VERSION 5.7 ;
  NOWIREEXTENSIONATPIN ON ;
  DIVIDERCHAR "/" ;
  BUSBITCHARS "[]" ;
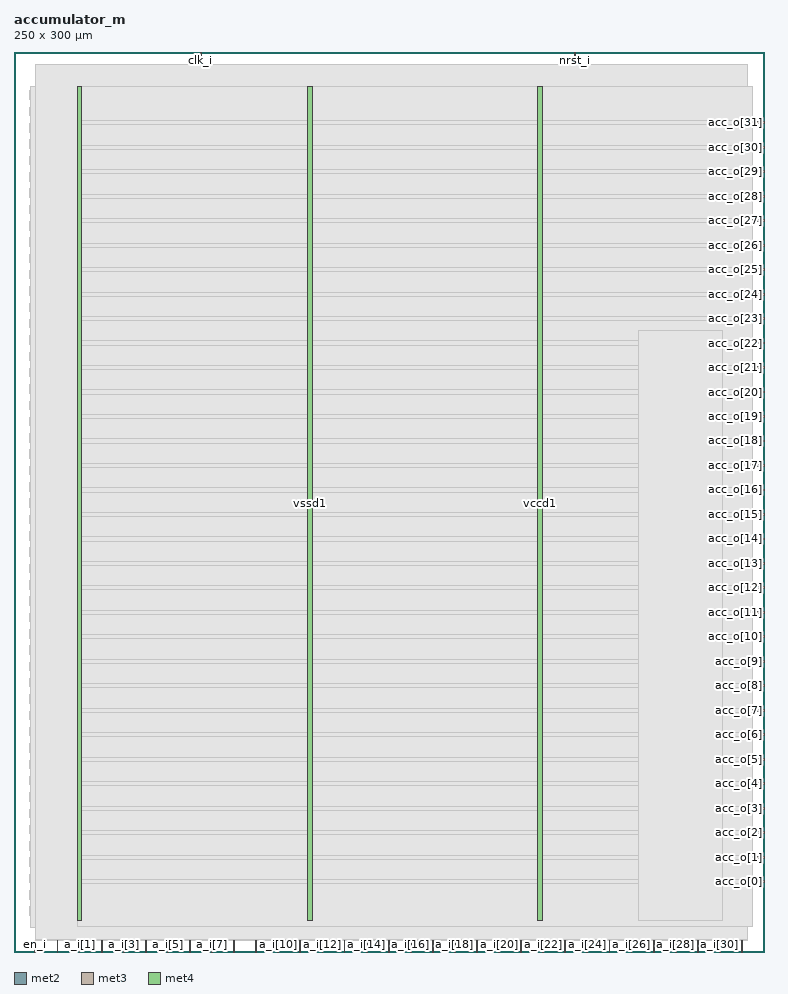
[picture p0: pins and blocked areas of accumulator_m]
MACRO accumulator_m
  CLASS BLOCK ;
  FOREIGN accumulator_m ;
  ORIGIN 0.000 0.000 ;
  SIZE 250.000 BY 300.000 ;
  PIN a_i[0]
    DIRECTION INPUT ;
    USE SIGNAL ;
    ANTENNAGATEAREA 0.213000 ;
    PORT
      LAYER met2 ;
        RECT 14.350 0.000 14.630 4.000 ;
    END
  END a_i[0]
  PIN a_i[10]
    DIRECTION INPUT ;
    USE SIGNAL ;
    ANTENNAGATEAREA 0.213000 ;
    PORT
      LAYER met2 ;
        RECT 87.950 0.000 88.230 4.000 ;
    END
  END a_i[10]
  PIN a_i[11]
    DIRECTION INPUT ;
    USE SIGNAL ;
    ANTENNAGATEAREA 0.126000 ;
    PORT
      LAYER met2 ;
        RECT 95.310 0.000 95.590 4.000 ;
    END
  END a_i[11]
  PIN a_i[12]
    DIRECTION INPUT ;
    USE SIGNAL ;
    ANTENNAGATEAREA 0.213000 ;
    PORT
      LAYER met2 ;
        RECT 102.670 0.000 102.950 4.000 ;
    END
  END a_i[12]
  PIN a_i[13]
    DIRECTION INPUT ;
    USE SIGNAL ;
    ANTENNAGATEAREA 0.213000 ;
    PORT
      LAYER met2 ;
        RECT 110.030 0.000 110.310 4.000 ;
    END
  END a_i[13]
  PIN a_i[14]
    DIRECTION INPUT ;
    USE SIGNAL ;
    ANTENNAGATEAREA 0.213000 ;
    PORT
      LAYER met2 ;
        RECT 117.390 0.000 117.670 4.000 ;
    END
  END a_i[14]
  PIN a_i[15]
    DIRECTION INPUT ;
    USE SIGNAL ;
    ANTENNAGATEAREA 0.213000 ;
    PORT
      LAYER met2 ;
        RECT 124.750 0.000 125.030 4.000 ;
    END
  END a_i[15]
  PIN a_i[16]
    DIRECTION INPUT ;
    USE SIGNAL ;
    ANTENNAGATEAREA 0.213000 ;
    PORT
      LAYER met2 ;
        RECT 132.110 0.000 132.390 4.000 ;
    END
  END a_i[16]
  PIN a_i[17]
    DIRECTION INPUT ;
    USE SIGNAL ;
    ANTENNAGATEAREA 0.213000 ;
    PORT
      LAYER met2 ;
        RECT 139.470 0.000 139.750 4.000 ;
    END
  END a_i[17]
  PIN a_i[18]
    DIRECTION INPUT ;
    USE SIGNAL ;
    ANTENNAGATEAREA 0.213000 ;
    PORT
      LAYER met2 ;
        RECT 146.830 0.000 147.110 4.000 ;
    END
  END a_i[18]
  PIN a_i[19]
    DIRECTION INPUT ;
    USE SIGNAL ;
    ANTENNAGATEAREA 0.126000 ;
    PORT
      LAYER met2 ;
        RECT 154.190 0.000 154.470 4.000 ;
    END
  END a_i[19]
  PIN a_i[1]
    DIRECTION INPUT ;
    USE SIGNAL ;
    ANTENNAGATEAREA 0.213000 ;
    PORT
      LAYER met2 ;
        RECT 21.710 0.000 21.990 4.000 ;
    END
  END a_i[1]
  PIN a_i[20]
    DIRECTION INPUT ;
    USE SIGNAL ;
    ANTENNAGATEAREA 0.196500 ;
    PORT
      LAYER met2 ;
        RECT 161.550 0.000 161.830 4.000 ;
    END
  END a_i[20]
  PIN a_i[21]
    DIRECTION INPUT ;
    USE SIGNAL ;
    ANTENNAGATEAREA 0.196500 ;
    PORT
      LAYER met2 ;
        RECT 168.910 0.000 169.190 4.000 ;
    END
  END a_i[21]
  PIN a_i[22]
    DIRECTION INPUT ;
    USE SIGNAL ;
    ANTENNAGATEAREA 0.196500 ;
    PORT
      LAYER met2 ;
        RECT 176.270 0.000 176.550 4.000 ;
    END
  END a_i[22]
  PIN a_i[23]
    DIRECTION INPUT ;
    USE SIGNAL ;
    ANTENNAGATEAREA 0.196500 ;
    PORT
      LAYER met2 ;
        RECT 183.630 0.000 183.910 4.000 ;
    END
  END a_i[23]
  PIN a_i[24]
    DIRECTION INPUT ;
    USE SIGNAL ;
    ANTENNAGATEAREA 0.196500 ;
    PORT
      LAYER met2 ;
        RECT 190.990 0.000 191.270 4.000 ;
    END
  END a_i[24]
  PIN a_i[25]
    DIRECTION INPUT ;
    USE SIGNAL ;
    ANTENNAGATEAREA 0.126000 ;
    PORT
      LAYER met2 ;
        RECT 198.350 0.000 198.630 4.000 ;
    END
  END a_i[25]
  PIN a_i[26]
    DIRECTION INPUT ;
    USE SIGNAL ;
    ANTENNAGATEAREA 0.196500 ;
    PORT
      LAYER met2 ;
        RECT 205.710 0.000 205.990 4.000 ;
    END
  END a_i[26]
  PIN a_i[27]
    DIRECTION INPUT ;
    USE SIGNAL ;
    ANTENNAGATEAREA 0.126000 ;
    PORT
      LAYER met2 ;
        RECT 213.070 0.000 213.350 4.000 ;
    END
  END a_i[27]
  PIN a_i[28]
    DIRECTION INPUT ;
    USE SIGNAL ;
    ANTENNAGATEAREA 0.196500 ;
    PORT
      LAYER met2 ;
        RECT 220.430 0.000 220.710 4.000 ;
    END
  END a_i[28]
  PIN a_i[29]
    DIRECTION INPUT ;
    USE SIGNAL ;
    ANTENNAGATEAREA 0.126000 ;
    PORT
      LAYER met2 ;
        RECT 227.790 0.000 228.070 4.000 ;
    END
  END a_i[29]
  PIN a_i[2]
    DIRECTION INPUT ;
    USE SIGNAL ;
    ANTENNAGATEAREA 0.213000 ;
    PORT
      LAYER met2 ;
        RECT 29.070 0.000 29.350 4.000 ;
    END
  END a_i[2]
  PIN a_i[30]
    DIRECTION INPUT ;
    USE SIGNAL ;
    ANTENNAGATEAREA 0.196500 ;
    PORT
      LAYER met2 ;
        RECT 235.150 0.000 235.430 4.000 ;
    END
  END a_i[30]
  PIN a_i[31]
    DIRECTION INPUT ;
    USE SIGNAL ;
    ANTENNAGATEAREA 0.196500 ;
    PORT
      LAYER met2 ;
        RECT 242.510 0.000 242.790 4.000 ;
    END
  END a_i[31]
  PIN a_i[3]
    DIRECTION INPUT ;
    USE SIGNAL ;
    ANTENNAGATEAREA 0.213000 ;
    PORT
      LAYER met2 ;
        RECT 36.430 0.000 36.710 4.000 ;
    END
  END a_i[3]
  PIN a_i[4]
    DIRECTION INPUT ;
    USE SIGNAL ;
    ANTENNAGATEAREA 0.213000 ;
    PORT
      LAYER met2 ;
        RECT 43.790 0.000 44.070 4.000 ;
    END
  END a_i[4]
  PIN a_i[5]
    DIRECTION INPUT ;
    USE SIGNAL ;
    ANTENNAGATEAREA 0.213000 ;
    PORT
      LAYER met2 ;
        RECT 51.150 0.000 51.430 4.000 ;
    END
  END a_i[5]
  PIN a_i[6]
    DIRECTION INPUT ;
    USE SIGNAL ;
    ANTENNAGATEAREA 0.213000 ;
    PORT
      LAYER met2 ;
        RECT 58.510 0.000 58.790 4.000 ;
    END
  END a_i[6]
  PIN a_i[7]
    DIRECTION INPUT ;
    USE SIGNAL ;
    ANTENNAGATEAREA 0.159000 ;
    PORT
      LAYER met2 ;
        RECT 65.870 0.000 66.150 4.000 ;
    END
  END a_i[7]
  PIN a_i[8]
    DIRECTION INPUT ;
    USE SIGNAL ;
    ANTENNAGATEAREA 0.213000 ;
    PORT
      LAYER met2 ;
        RECT 73.230 0.000 73.510 4.000 ;
    END
  END a_i[8]
  PIN a_i[9]
    DIRECTION INPUT ;
    USE SIGNAL ;
    ANTENNAGATEAREA 0.213000 ;
    PORT
      LAYER met2 ;
        RECT 80.590 0.000 80.870 4.000 ;
    END
  END a_i[9]
  PIN acc_o[0]
    DIRECTION OUTPUT TRISTATE ;
    USE SIGNAL ;
    ANTENNADIFFAREA 2.673000 ;
    PORT
      LAYER met3 ;
        RECT 246.000 23.160 250.000 23.760 ;
    END
  END acc_o[0]
  PIN acc_o[10]
    DIRECTION OUTPUT TRISTATE ;
    USE SIGNAL ;
    ANTENNADIFFAREA 2.673000 ;
    PORT
      LAYER met3 ;
        RECT 246.000 104.760 250.000 105.360 ;
    END
  END acc_o[10]
  PIN acc_o[11]
    DIRECTION OUTPUT TRISTATE ;
    USE SIGNAL ;
    ANTENNADIFFAREA 2.673000 ;
    PORT
      LAYER met3 ;
        RECT 246.000 112.920 250.000 113.520 ;
    END
  END acc_o[11]
  PIN acc_o[12]
    DIRECTION OUTPUT TRISTATE ;
    USE SIGNAL ;
    ANTENNADIFFAREA 2.673000 ;
    PORT
      LAYER met3 ;
        RECT 246.000 121.080 250.000 121.680 ;
    END
  END acc_o[12]
  PIN acc_o[13]
    DIRECTION OUTPUT TRISTATE ;
    USE SIGNAL ;
    ANTENNADIFFAREA 2.673000 ;
    PORT
      LAYER met3 ;
        RECT 246.000 129.240 250.000 129.840 ;
    END
  END acc_o[13]
  PIN acc_o[14]
    DIRECTION OUTPUT TRISTATE ;
    USE SIGNAL ;
    ANTENNADIFFAREA 2.673000 ;
    PORT
      LAYER met3 ;
        RECT 246.000 137.400 250.000 138.000 ;
    END
  END acc_o[14]
  PIN acc_o[15]
    DIRECTION OUTPUT TRISTATE ;
    USE SIGNAL ;
    ANTENNADIFFAREA 2.673000 ;
    PORT
      LAYER met3 ;
        RECT 246.000 145.560 250.000 146.160 ;
    END
  END acc_o[15]
  PIN acc_o[16]
    DIRECTION OUTPUT TRISTATE ;
    USE SIGNAL ;
    ANTENNADIFFAREA 2.673000 ;
    PORT
      LAYER met3 ;
        RECT 246.000 153.720 250.000 154.320 ;
    END
  END acc_o[16]
  PIN acc_o[17]
    DIRECTION OUTPUT TRISTATE ;
    USE SIGNAL ;
    ANTENNADIFFAREA 2.673000 ;
    PORT
      LAYER met3 ;
        RECT 246.000 161.880 250.000 162.480 ;
    END
  END acc_o[17]
  PIN acc_o[18]
    DIRECTION OUTPUT TRISTATE ;
    USE SIGNAL ;
    ANTENNADIFFAREA 2.673000 ;
    PORT
      LAYER met3 ;
        RECT 246.000 170.040 250.000 170.640 ;
    END
  END acc_o[18]
  PIN acc_o[19]
    DIRECTION OUTPUT TRISTATE ;
    USE SIGNAL ;
    ANTENNADIFFAREA 2.673000 ;
    PORT
      LAYER met3 ;
        RECT 246.000 178.200 250.000 178.800 ;
    END
  END acc_o[19]
  PIN acc_o[1]
    DIRECTION OUTPUT TRISTATE ;
    USE SIGNAL ;
    ANTENNADIFFAREA 2.673000 ;
    PORT
      LAYER met3 ;
        RECT 246.000 31.320 250.000 31.920 ;
    END
  END acc_o[1]
  PIN acc_o[20]
    DIRECTION OUTPUT TRISTATE ;
    USE SIGNAL ;
    ANTENNADIFFAREA 2.673000 ;
    PORT
      LAYER met3 ;
        RECT 246.000 186.360 250.000 186.960 ;
    END
  END acc_o[20]
  PIN acc_o[21]
    DIRECTION OUTPUT TRISTATE ;
    USE SIGNAL ;
    ANTENNADIFFAREA 2.673000 ;
    PORT
      LAYER met3 ;
        RECT 246.000 194.520 250.000 195.120 ;
    END
  END acc_o[21]
  PIN acc_o[22]
    DIRECTION OUTPUT TRISTATE ;
    USE SIGNAL ;
    ANTENNADIFFAREA 2.673000 ;
    PORT
      LAYER met3 ;
        RECT 246.000 202.680 250.000 203.280 ;
    END
  END acc_o[22]
  PIN acc_o[23]
    DIRECTION OUTPUT TRISTATE ;
    USE SIGNAL ;
    ANTENNADIFFAREA 2.673000 ;
    PORT
      LAYER met3 ;
        RECT 246.000 210.840 250.000 211.440 ;
    END
  END acc_o[23]
  PIN acc_o[24]
    DIRECTION OUTPUT TRISTATE ;
    USE SIGNAL ;
    ANTENNADIFFAREA 2.673000 ;
    PORT
      LAYER met3 ;
        RECT 246.000 219.000 250.000 219.600 ;
    END
  END acc_o[24]
  PIN acc_o[25]
    DIRECTION OUTPUT TRISTATE ;
    USE SIGNAL ;
    ANTENNADIFFAREA 2.673000 ;
    PORT
      LAYER met3 ;
        RECT 246.000 227.160 250.000 227.760 ;
    END
  END acc_o[25]
  PIN acc_o[26]
    DIRECTION OUTPUT TRISTATE ;
    USE SIGNAL ;
    ANTENNADIFFAREA 2.673000 ;
    PORT
      LAYER met3 ;
        RECT 246.000 235.320 250.000 235.920 ;
    END
  END acc_o[26]
  PIN acc_o[27]
    DIRECTION OUTPUT TRISTATE ;
    USE SIGNAL ;
    ANTENNADIFFAREA 2.673000 ;
    PORT
      LAYER met3 ;
        RECT 246.000 243.480 250.000 244.080 ;
    END
  END acc_o[27]
  PIN acc_o[28]
    DIRECTION OUTPUT TRISTATE ;
    USE SIGNAL ;
    ANTENNADIFFAREA 2.673000 ;
    PORT
      LAYER met3 ;
        RECT 246.000 251.640 250.000 252.240 ;
    END
  END acc_o[28]
  PIN acc_o[29]
    DIRECTION OUTPUT TRISTATE ;
    USE SIGNAL ;
    ANTENNADIFFAREA 2.673000 ;
    PORT
      LAYER met3 ;
        RECT 246.000 259.800 250.000 260.400 ;
    END
  END acc_o[29]
  PIN acc_o[2]
    DIRECTION OUTPUT TRISTATE ;
    USE SIGNAL ;
    ANTENNADIFFAREA 2.673000 ;
    PORT
      LAYER met3 ;
        RECT 246.000 39.480 250.000 40.080 ;
    END
  END acc_o[2]
  PIN acc_o[30]
    DIRECTION OUTPUT TRISTATE ;
    USE SIGNAL ;
    ANTENNADIFFAREA 2.673000 ;
    PORT
      LAYER met3 ;
        RECT 246.000 267.960 250.000 268.560 ;
    END
  END acc_o[30]
  PIN acc_o[31]
    DIRECTION OUTPUT TRISTATE ;
    USE SIGNAL ;
    ANTENNADIFFAREA 2.673000 ;
    PORT
      LAYER met3 ;
        RECT 246.000 276.120 250.000 276.720 ;
    END
  END acc_o[31]
  PIN acc_o[3]
    DIRECTION OUTPUT TRISTATE ;
    USE SIGNAL ;
    ANTENNADIFFAREA 2.673000 ;
    PORT
      LAYER met3 ;
        RECT 246.000 47.640 250.000 48.240 ;
    END
  END acc_o[3]
  PIN acc_o[4]
    DIRECTION OUTPUT TRISTATE ;
    USE SIGNAL ;
    ANTENNADIFFAREA 2.673000 ;
    PORT
      LAYER met3 ;
        RECT 246.000 55.800 250.000 56.400 ;
    END
  END acc_o[4]
  PIN acc_o[5]
    DIRECTION OUTPUT TRISTATE ;
    USE SIGNAL ;
    ANTENNADIFFAREA 2.673000 ;
    PORT
      LAYER met3 ;
        RECT 246.000 63.960 250.000 64.560 ;
    END
  END acc_o[5]
  PIN acc_o[6]
    DIRECTION OUTPUT TRISTATE ;
    USE SIGNAL ;
    ANTENNADIFFAREA 2.673000 ;
    PORT
      LAYER met3 ;
        RECT 246.000 72.120 250.000 72.720 ;
    END
  END acc_o[6]
  PIN acc_o[7]
    DIRECTION OUTPUT TRISTATE ;
    USE SIGNAL ;
    ANTENNADIFFAREA 2.673000 ;
    PORT
      LAYER met3 ;
        RECT 246.000 80.280 250.000 80.880 ;
    END
  END acc_o[7]
  PIN acc_o[8]
    DIRECTION OUTPUT TRISTATE ;
    USE SIGNAL ;
    ANTENNADIFFAREA 2.673000 ;
    PORT
      LAYER met3 ;
        RECT 246.000 88.440 250.000 89.040 ;
    END
  END acc_o[8]
  PIN acc_o[9]
    DIRECTION OUTPUT TRISTATE ;
    USE SIGNAL ;
    ANTENNADIFFAREA 2.673000 ;
    PORT
      LAYER met3 ;
        RECT 246.000 96.600 250.000 97.200 ;
    END
  END acc_o[9]
  PIN clk_i
    DIRECTION INPUT ;
    USE SIGNAL ;
    ANTENNAGATEAREA 0.852000 ;
    PORT
      LAYER met2 ;
        RECT 62.190 296.000 62.470 300.000 ;
    END
  END clk_i
  PIN en_i
    DIRECTION INPUT ;
    USE SIGNAL ;
    ANTENNAGATEAREA 0.213000 ;
    PORT
      LAYER met2 ;
        RECT 6.990 0.000 7.270 4.000 ;
    END
  END en_i
  PIN nrst_i
    DIRECTION INPUT ;
    USE SIGNAL ;
    ANTENNAGATEAREA 0.213000 ;
    PORT
      LAYER met2 ;
        RECT 186.850 296.000 187.130 300.000 ;
    END
  END nrst_i
  PIN vccd1
    DIRECTION INOUT ;
    USE POWER ;
    PORT
      LAYER met4 ;
        RECT 21.040 10.640 22.640 288.560 ;
    END
    PORT
      LAYER met4 ;
        RECT 174.640 10.640 176.240 288.560 ;
    END
  END vccd1
  PIN vssd1
    DIRECTION INOUT ;
    USE GROUND ;
    PORT
      LAYER met4 ;
        RECT 97.840 10.640 99.440 288.560 ;
    END
  END vssd1
  OBS
      LAYER nwell ;
        RECT 5.330 284.185 244.450 287.015 ;
        RECT 5.330 278.745 244.450 281.575 ;
        RECT 5.330 273.305 244.450 276.135 ;
        RECT 5.330 267.865 244.450 270.695 ;
        RECT 5.330 262.425 244.450 265.255 ;
        RECT 5.330 256.985 244.450 259.815 ;
        RECT 5.330 251.545 244.450 254.375 ;
        RECT 5.330 246.105 244.450 248.935 ;
        RECT 5.330 240.665 244.450 243.495 ;
        RECT 5.330 235.225 244.450 238.055 ;
        RECT 5.330 229.785 244.450 232.615 ;
        RECT 5.330 224.345 244.450 227.175 ;
        RECT 5.330 218.905 244.450 221.735 ;
        RECT 5.330 213.465 244.450 216.295 ;
        RECT 5.330 208.025 244.450 210.855 ;
        RECT 5.330 202.585 244.450 205.415 ;
        RECT 5.330 197.145 244.450 199.975 ;
        RECT 5.330 191.705 244.450 194.535 ;
        RECT 5.330 186.265 244.450 189.095 ;
        RECT 5.330 180.825 244.450 183.655 ;
        RECT 5.330 175.385 244.450 178.215 ;
        RECT 5.330 169.945 244.450 172.775 ;
        RECT 5.330 164.505 244.450 167.335 ;
        RECT 5.330 159.065 244.450 161.895 ;
        RECT 5.330 153.625 244.450 156.455 ;
        RECT 5.330 148.185 244.450 151.015 ;
        RECT 5.330 142.745 244.450 145.575 ;
        RECT 5.330 137.305 244.450 140.135 ;
        RECT 5.330 131.865 244.450 134.695 ;
        RECT 5.330 126.425 244.450 129.255 ;
        RECT 5.330 120.985 244.450 123.815 ;
        RECT 5.330 115.545 244.450 118.375 ;
        RECT 5.330 110.105 244.450 112.935 ;
        RECT 5.330 104.665 244.450 107.495 ;
        RECT 5.330 99.225 244.450 102.055 ;
        RECT 5.330 93.785 244.450 96.615 ;
        RECT 5.330 88.345 244.450 91.175 ;
        RECT 5.330 82.905 244.450 85.735 ;
        RECT 5.330 77.465 244.450 80.295 ;
        RECT 5.330 72.025 244.450 74.855 ;
        RECT 5.330 66.585 244.450 69.415 ;
        RECT 5.330 61.145 244.450 63.975 ;
        RECT 5.330 55.705 244.450 58.535 ;
        RECT 5.330 50.265 244.450 53.095 ;
        RECT 5.330 44.825 244.450 47.655 ;
        RECT 5.330 39.385 244.450 42.215 ;
        RECT 5.330 33.945 244.450 36.775 ;
        RECT 5.330 28.505 244.450 31.335 ;
        RECT 5.330 23.065 244.450 25.895 ;
        RECT 5.330 17.625 244.450 20.455 ;
        RECT 5.330 12.185 244.450 15.015 ;
      LAYER li1 ;
        RECT 5.520 10.795 244.260 288.405 ;
      LAYER met1 ;
        RECT 5.520 8.200 244.560 288.560 ;
      LAYER met2 ;
        RECT 7.060 295.720 61.910 296.000 ;
        RECT 62.750 295.720 186.570 296.000 ;
        RECT 187.410 295.720 244.560 296.000 ;
        RECT 7.060 4.280 244.560 295.720 ;
        RECT 7.550 4.000 14.070 4.280 ;
        RECT 14.910 4.000 21.430 4.280 ;
        RECT 22.270 4.000 28.790 4.280 ;
        RECT 29.630 4.000 36.150 4.280 ;
        RECT 36.990 4.000 43.510 4.280 ;
        RECT 44.350 4.000 50.870 4.280 ;
        RECT 51.710 4.000 58.230 4.280 ;
        RECT 59.070 4.000 65.590 4.280 ;
        RECT 66.430 4.000 72.950 4.280 ;
        RECT 73.790 4.000 80.310 4.280 ;
        RECT 81.150 4.000 87.670 4.280 ;
        RECT 88.510 4.000 95.030 4.280 ;
        RECT 95.870 4.000 102.390 4.280 ;
        RECT 103.230 4.000 109.750 4.280 ;
        RECT 110.590 4.000 117.110 4.280 ;
        RECT 117.950 4.000 124.470 4.280 ;
        RECT 125.310 4.000 131.830 4.280 ;
        RECT 132.670 4.000 139.190 4.280 ;
        RECT 140.030 4.000 146.550 4.280 ;
        RECT 147.390 4.000 153.910 4.280 ;
        RECT 154.750 4.000 161.270 4.280 ;
        RECT 162.110 4.000 168.630 4.280 ;
        RECT 169.470 4.000 175.990 4.280 ;
        RECT 176.830 4.000 183.350 4.280 ;
        RECT 184.190 4.000 190.710 4.280 ;
        RECT 191.550 4.000 198.070 4.280 ;
        RECT 198.910 4.000 205.430 4.280 ;
        RECT 206.270 4.000 212.790 4.280 ;
        RECT 213.630 4.000 220.150 4.280 ;
        RECT 220.990 4.000 227.510 4.280 ;
        RECT 228.350 4.000 234.870 4.280 ;
        RECT 235.710 4.000 242.230 4.280 ;
        RECT 243.070 4.000 244.560 4.280 ;
      LAYER met3 ;
        RECT 21.050 277.120 246.000 288.485 ;
        RECT 21.050 275.720 245.600 277.120 ;
        RECT 21.050 268.960 246.000 275.720 ;
        RECT 21.050 267.560 245.600 268.960 ;
        RECT 21.050 260.800 246.000 267.560 ;
        RECT 21.050 259.400 245.600 260.800 ;
        RECT 21.050 252.640 246.000 259.400 ;
        RECT 21.050 251.240 245.600 252.640 ;
        RECT 21.050 244.480 246.000 251.240 ;
        RECT 21.050 243.080 245.600 244.480 ;
        RECT 21.050 236.320 246.000 243.080 ;
        RECT 21.050 234.920 245.600 236.320 ;
        RECT 21.050 228.160 246.000 234.920 ;
        RECT 21.050 226.760 245.600 228.160 ;
        RECT 21.050 220.000 246.000 226.760 ;
        RECT 21.050 218.600 245.600 220.000 ;
        RECT 21.050 211.840 246.000 218.600 ;
        RECT 21.050 210.440 245.600 211.840 ;
        RECT 21.050 203.680 246.000 210.440 ;
        RECT 21.050 202.280 245.600 203.680 ;
        RECT 21.050 195.520 246.000 202.280 ;
        RECT 21.050 194.120 245.600 195.520 ;
        RECT 21.050 187.360 246.000 194.120 ;
        RECT 21.050 185.960 245.600 187.360 ;
        RECT 21.050 179.200 246.000 185.960 ;
        RECT 21.050 177.800 245.600 179.200 ;
        RECT 21.050 171.040 246.000 177.800 ;
        RECT 21.050 169.640 245.600 171.040 ;
        RECT 21.050 162.880 246.000 169.640 ;
        RECT 21.050 161.480 245.600 162.880 ;
        RECT 21.050 154.720 246.000 161.480 ;
        RECT 21.050 153.320 245.600 154.720 ;
        RECT 21.050 146.560 246.000 153.320 ;
        RECT 21.050 145.160 245.600 146.560 ;
        RECT 21.050 138.400 246.000 145.160 ;
        RECT 21.050 137.000 245.600 138.400 ;
        RECT 21.050 130.240 246.000 137.000 ;
        RECT 21.050 128.840 245.600 130.240 ;
        RECT 21.050 122.080 246.000 128.840 ;
        RECT 21.050 120.680 245.600 122.080 ;
        RECT 21.050 113.920 246.000 120.680 ;
        RECT 21.050 112.520 245.600 113.920 ;
        RECT 21.050 105.760 246.000 112.520 ;
        RECT 21.050 104.360 245.600 105.760 ;
        RECT 21.050 97.600 246.000 104.360 ;
        RECT 21.050 96.200 245.600 97.600 ;
        RECT 21.050 89.440 246.000 96.200 ;
        RECT 21.050 88.040 245.600 89.440 ;
        RECT 21.050 81.280 246.000 88.040 ;
        RECT 21.050 79.880 245.600 81.280 ;
        RECT 21.050 73.120 246.000 79.880 ;
        RECT 21.050 71.720 245.600 73.120 ;
        RECT 21.050 64.960 246.000 71.720 ;
        RECT 21.050 63.560 245.600 64.960 ;
        RECT 21.050 56.800 246.000 63.560 ;
        RECT 21.050 55.400 245.600 56.800 ;
        RECT 21.050 48.640 246.000 55.400 ;
        RECT 21.050 47.240 245.600 48.640 ;
        RECT 21.050 40.480 246.000 47.240 ;
        RECT 21.050 39.080 245.600 40.480 ;
        RECT 21.050 32.320 246.000 39.080 ;
        RECT 21.050 30.920 245.600 32.320 ;
        RECT 21.050 24.160 246.000 30.920 ;
        RECT 21.050 22.760 245.600 24.160 ;
        RECT 21.050 8.335 246.000 22.760 ;
      LAYER met4 ;
        RECT 208.215 10.375 236.145 207.225 ;
  END
END accumulator_m
END LIBRARY

